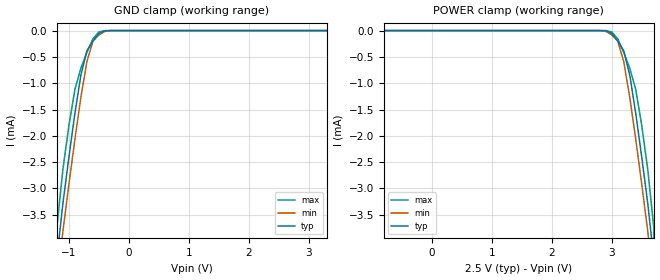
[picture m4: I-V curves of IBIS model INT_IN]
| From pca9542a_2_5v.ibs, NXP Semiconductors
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[Model]   INT_IN
Model_type Input
Vinh=2.1
Vinl=0.9
C_comp   1.73p   1.73p   1.73p
[Temperature Range] 27   85   -40
[Voltage Range]   2.5   2.25   2.75
[POWER Clamp Reference]2.5   2.25   2.75
[GND Clamp Reference]0   0   0
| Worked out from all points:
|   GND clamp passes 1 mA (typ) near -0.82 V on its own axis
[GND Clamp]
-2.5V     -19.92A    -18.71A    -21.43A
-1.3V     -11.85mA   -8.952mA   -32.91mA
-1.2V     -4.325mA   -4.839mA   -3.732mA
-1.1V     -3.285mA   -3.811mA   -2.639mA
-1V       -2.406mA   -2.922mA   -1.806mA
-900mV    -1.574mA   -2.066mA   -1.116mA
-800mV    -845.7uA   -1.265mA   -715.4uA
-700mV    -384.1uA   -589.5uA   -416uA
-600mV    -196.2uA   -202.7uA   -157.7uA
-500mV    -54.35uA   -83.42uA   -25.32uA
-300mV    -137.5nA   -707nA     -7.814nA
3.3V      10.8pA     23.25pA    9.906pA
[POWER Clamp]
-800mV    10.8pA     23.25pA    9.906pA
2.8V      -137.5nA   -707nA     -7.815nA
3V        -54.35uA   -83.42uA   -25.32uA
3.1V      -196.2uA   -202.7uA   -157.7uA
3.2V      -384.1uA   -589.5uA   -416uA
3.3V      -845.7uA   -1.265mA   -715.4uA
3.4V      -1.574mA   -2.066mA   -1.116mA
3.5V      -2.406mA   -2.922mA   -1.806mA
3.6V      -3.285mA   -3.811mA   -2.639mA
3.7V      -4.325mA   -4.839mA   -3.732mA
3.8V      -11.85mA   -8.952mA   -32.91mA
5V        -19.92A    -18.71A    -21.43A
